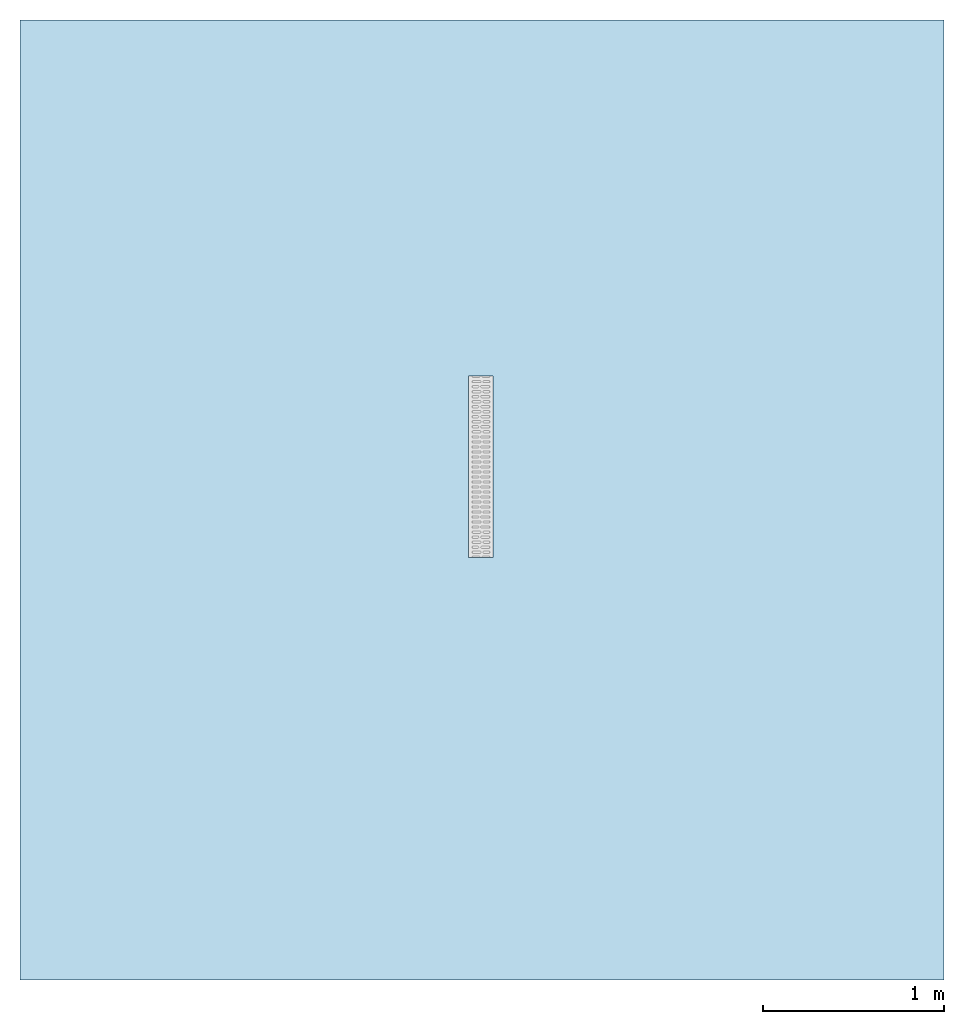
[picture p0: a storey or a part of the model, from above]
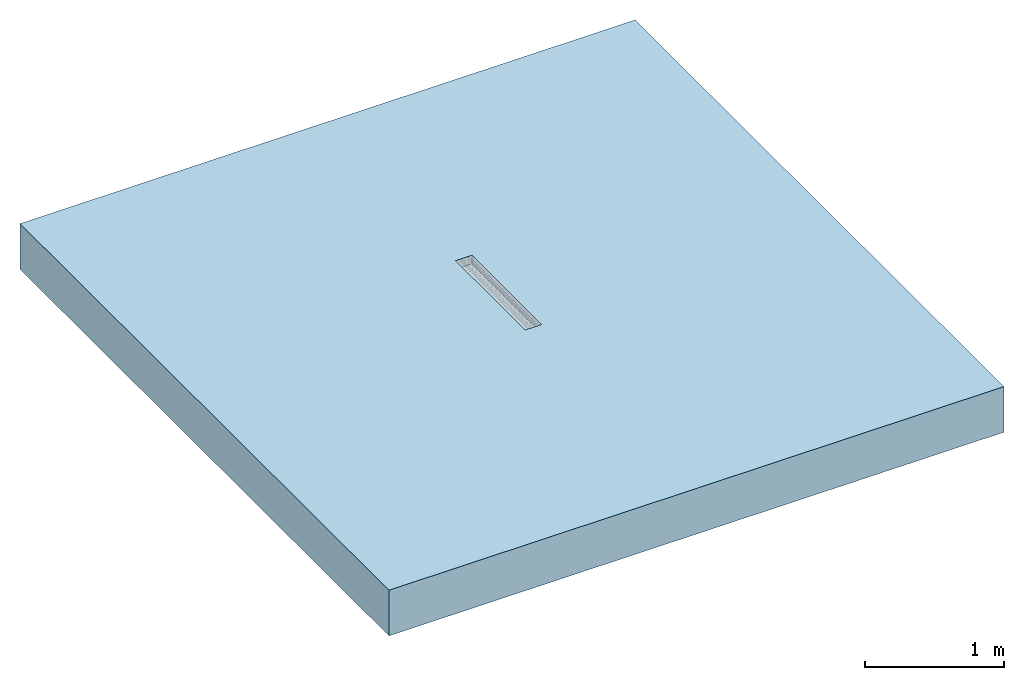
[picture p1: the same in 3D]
Properties of the parts of a building model (IFC2X3)

# File
Description: ViewDefinition [CoordinationView]
File name: 23075 - No 075 Constant Depth Channel - 1000mm LG - Invert Depth 55mm.ifc
Time: 2013-10-16T12:14:03
Written by: Autodesk Revit 2013
Made in: 20120221_2030(x64)

# IfcProject, Project Number
LongName: Project Name; Phase: Project Status

# IfcSite, Default
RefLatitude: 42, 21, 30, 344238; RefLongitude: -71, -3, -35, -194702; RefElevation: 0 mm

# IfcBuilding
Pset_BuildingCommon - NumberOfStoreys: 1
Other - Project Address: ## Street City, State Zip; Client Name: Owner; Project Name: Project Name; Project Number: Project Number; Project Issue Date: Issue Date; Project Status: Project Status

# IfcBuildingStorey, Level 1
LongName: Level 1; Elevation: 0 mm
Graphics - Line Weight: 1; Symbol: M_Level Head - Circle: M_Level Head - Circle; Symbol at End 1 Default: no; Line Pattern: Center; Color: 0; Symbol at End 2 Default: yes
Constraints - Elevation Base: 0; Elevation: 0 mm
Dimensions - Computation Height: 0 mm
Identity Data - Name: Level 1; Structural: no; Building Story: yes

# IfcBuildingElementProxy: 23075 - No 075 Constant Depth Channel - 1000mm LG - Invert Depth 55mm, Civil-Drainage-Channel-ACO-MultiDrain-M100D-Channel-System:23075 - No 075 Constant Depth Channel - 1000mm LG - Invert Depth 55mm:23075 - No 075 Constant Depth Channel - 1000mm LG - Invert Depth 55mm:1089344
In: Level 1
Material: Vienite® Synthetic Resin Concrete
Construction - 23409 - Grating - ATec coated - Heelguard™ - Ductile Iron - 500mm Long: no; 12618 - Grating - Mesh - Galvanised Steel - 1000mm Long: no; 12680 - Grating - Heelguard™ - Composite Black - 500mm Long: no; 23406 - Grating - Solid Cover - Ductile Iron - 500mm Long: no; 12657 - Grating - Perforated - Galvanised Steel - 500mm long: no; 12673 - Grating - Intercept - Ductile Iron - 500mm Long: no; 23405 - Grating - Heelguard™ - Ductile Iron - 500mm Long: no; 23408 - Grating - Slotted - Ductile Iron - 500mm Long: no; 12610 - Grating - Slotted - Galvanised Steel - 1000mm Long: no; 12656 - Grating - Perforated - Galvanised Steel - 1000mm long: no; 12667 - Grating - Perforated - Galvanised Steel - 500mm Long: no; 12615 - Grating - Slotted - Galvanised Steel - 500mm Long: no; 23404 - Universal Endcap - Male End: no; 12619 - Grating - Mesh - Galvanised Steel - 500mm Long: no; 23404 - Universal Endcap - Female End: no; 12611 - Grating - Slotted - Galvanised Steel - 500mm Long: no; 12666 - Grating - Perforated - Galvanised Steel - 1000mm Long: no; 12614 - Grating - Slotted - Galvanised Steel - 1000mm Long: no; Constant Depth Channel: no; Sloping Channel: no; 23453 - Kerb Outlet Bull Nose: no; 23451 - Downpipe connector 100mm Depth: no; Sump Unit: no; 23450 - Downpipe connector 75mm Depth: no; 23452 - Kerb Outlet Half Batter: no; Shallow Depth Channel with seal: no; Shallow Depth Channel: yes; Constant Depth Junction Channel: no; Grating 1000mm: yes
Dimensions - FloorCut_Length: -1000 mm; Custom_Value_Length: 0 mm; Length: 1000 mm; Volume: 5923550 mm3; EndCap Position: 1000 mm; Length Drain: -1000 mm; Endcap_Void_Depth: 0 mm; Depth: 150 mm; ShallowInvDepth: 55 mm; FloorCut_Width: 135 mm; SlopingEndInvertDepth: 180 mm; SlopingInvertDepth: 175 mm; EndCap_Female_Height: 75 mm; InvDepth: 80 mm; SlopingOverallDepth: 245 mm; EndCap_Height: 75 mm; FloorCut_HorPosition: 67.5 mm; FloorCut_Depth: 75 mm; ShallowOverallDepth: 75 mm; SlopingEndOverallDepth: 250 mm
Phasing - Phase Created: New Construction
Constraints - Moves With Nearby Elements: no; Level: Level: Level 1
Pset_BuildingElementProxyCommon - Reference: 23075 - No 075 Constant Depth Channel - 1000mm LG - Invert Depth 55mm
Model Properties - Grating Product code 12618: Load Class C250 - Meshed Galvanised Steel 410DL 1000mm long - 25x12mm slot - Intake Area 88000mm²/m - 3.1kg; Grating Product code 12615: Load Class C250 - Slotted Galvanised Steel 424DL 500mm long- 10mm slot - Intake Area 31200mm²/m - 2.2kg; Grating Product code 12667: Load Class A15 - Perforated Galvanised Steel 12667DL - 500mm long - 6mm hole - Intake Area 17800mm²/m - 1kg; Grating Product code 12673: Load Class C250 - Intercept Ductile Iron 507DL - 500mm long - 31x12mm slot - Intake Area 43000mm²/m - 3.5kg; Grating Product code 12614: Load Class C250 - Slotted Galvanised Steel 423DL 1000mm long- 10mm slot - Intake Area 31200mm²/m - 4.3kg; Grating Product code 23406: Load Class D400 - Solid Cover Ductile Iron 23406DL - 500mm long - 4.5kg; Grating Product code 12619: Load Class C250 - Meshed Steel 412DL 500mm long- 25x12mm slot - Intake Area 88000mm²/m - 1.5kg; Grating Product code 23408: Load Class D400 - Intercept Ductile Iron 507DL - 500mm long - 12mm slot - Intake Area 36200mm²/m - 3.8kg; Grating Product code 12666: Load Class A15 - Perforated Galvanised Steel 12666DL - 1000mm long - 6mm hole - Intake Area 17800mm²/m - 2.2kg; End Cap Product code 23404: No. 306 Universal End Cap - 135mm wide x 300mm long - Spigot Ø110mm x 50mm long - Silver - Polypropylene - 0.16kg; Grating Product code 12611: Load Class A15 - Slotted Galvanised Steel 402DL - 500mm long - 10mm slot - Intake Area 31200mm²/m - 1kg; Grating Product code 23405: Load Class D400 - Heelguard Ductile Iron 23405DL - 500mm long - 8mm slot - Intake Area 25400mm²/m - 4.2kg; Grating Product code 12610: Load Class A15 - Slotted Galvanised Steel 400DL - 1000mm long - 10mm slot - Intake Area 31200mm²/m - 2.2kg; Grating Product code 12656: Load Class C250 - Perforated Galvanised Steel 12656DL 1000mm long - 6mm hole - Intake Area 17800mm²/m - 4.8kg; Grating Product code 23409: Load Class D400 - ATec coated Heelguard Ductile Iron 23409DL - 500mm long - 8mm slot - Intake Area 25400mm²/m - 4.2kg; Grating Product code 12657: Load Class C250 - Perforated Galvanised Steel 12657DL 500mm long- 6mm hole - Intake Area 17800mm²/m - 2.4kg; Grating Product code 12680: Load Class C250 - Heelguard Composite Black 522DL - 500mm long - 8mm slot - Intake Area 14250mm²/m - 1.2kg
Data - ACO Hydraulic Design Software: http://www.acodesign.co.uk; Concrete Surround Volume - Load Class A 15 - Concrete Pavement: 0.05m³/m; Product Weight: 9.2 Kg; Product Standard: BS EN 1433:2002, CE marked; Pre-formed Outlet Ø: N/A; Installation - Concrete Grade: Refer to brochure; Product Dimensions: 1000mm x 135mm x 75mm (LxWxH); Concrete Surround Volume - Load Class D 400 - Concrete Pavement: 0.14m³/m; Invert Depth: 55mm; Concrete Surround Volume - Load Class B 125 - C 250 - Concrete Pavement: 0.09m³/m; Hydraulic Performance: http://www.aco.co.uk/download.php?id=173; Load Class: A 15 - D 400; Channel C.S.A: 0.0034m²
General - TagNumber: 0; SerialNumber: 0
Identity Data - Installation guidelines: http://www.aco.co.uk/download.php?id=173; Telephone: +44 (0)1462 816666; Maintenance guidelines: http://www.aco.co.uk/download.php?id=173; Watermarked With: BIM Manager Premium Suite; Product Code: 23075; URL: www.aco.co.uk; Model: ACO MultiDrain MD - M100D; Manufacturer: ACO Technologies plc - ACO Water Management Division; Type Comments: ACO MultiDrain M100D No 075 Constant Depth Shallow Channel 1000mm Long; Cost: 0; Model Description: Channel drainage system; Watermark 2: This file is watermarked and users are prohibited to reproduce, adapt, distribute this information; OmniClass Title: Rainwater Removal; Watermark 1: This file is the property of ACO Technologies PLC; e-mail Technical: technical@aco.co.uk; Watermarked By: www.aco.co.uk; OmniClass Number: 23.70.50.24; Address: ACO Business Park, Hitchin Road, Shefford, Bedfordshire, United Kingdom SG17 5TE; Fax: +44 (0)1462 815895; Product brochure: http://www.aco.co.uk/download.php?id=173; Product Page URL: http://www.aco.co.uk/product_detail.php?id=15; Assembly Code: D2040; Assembly Description: Rain Water Drainage; Price: POA - contact ACO; e-mail Sales: customersupport@aco.co.uk
Materials and Finishes - Channel Material: Vienite® Synthetic Resin Concrete; Channel Colour: Brown; Edge Rail Finish: Pre-galvanised; Edge Rail Colour: Silver; Edge Rail Material: Steel
Other - Revision: 1; CreatedBy: www.aco.co.uk
Green Building Properties - Channel Recyclable: Fully recyclable; Channel Recycled Material Content: 20% minimum; Edge Rail Recyclable: Fully recyclable; Edge Rail Recycled Material Content: Between 40% - 90%

# IfcOpeningElement: Recess
In: Level 1
Dimensions - Perimeter: 20800 mm; Area: 27030000 mm2; Volume: 10801875000 mm3; Thickness: 400 mm
Phasing - Phase Created: New Construction
Structural - Structural: no; Enable Analytical Model: no
Constraints - Related to Mass: no; Room Bounding: yes; Level: Level: Level 1; Height Offset From Level: 0 mm
Analytical Properties - Absorptance: 0.1; Roughness: 1
Construction - Function: 0; Default Thickness: 400 mm
Materials and Finishes - Structural Material: Plant
Graphics - Coarse Scale Fill Color: 0

# IfcSlab: Floor:Generic Floor - 400mm, Floor:Generic Floor - 400mm:193825
In: Level 1
PredefinedType: FLOOR; Material: Plant 400 mm
Dimensions - Perimeter: 20800 mm; Area: 27030000 mm2; Volume: 10801875000 mm3; Thickness: 400 mm
Phasing - Phase Created: New Construction
Structural - Structural: no; Enable Analytical Model: no
Constraints - Related to Mass: no; Room Bounding: yes; Level: Level: Level 1; Height Offset From Level: 0 mm
Pset_SlabCommon - Reference: Generic Floor - 400mm; IsExternal: no; LoadBearing: yes
Analytical Properties - Absorptance: 0.1; Roughness: 1
Construction - Function: 0; Default Thickness: 400 mm
Materials and Finishes - Structural Material: Plant
Graphics - Coarse Scale Fill Color: 0
